One B-rep face of a CAD part: STEP entity #1033.
In plain terms, the planar face has unit normal (1, 0, 0).
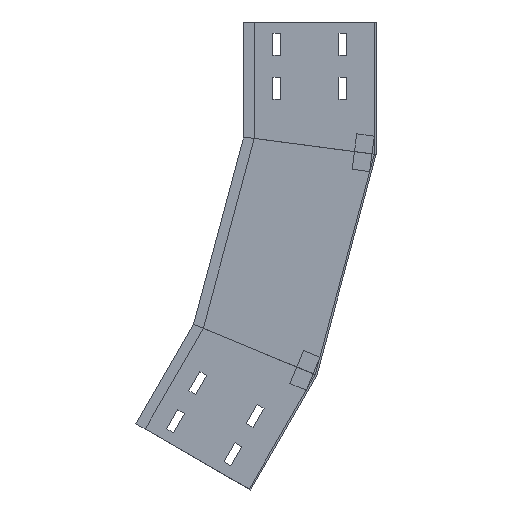
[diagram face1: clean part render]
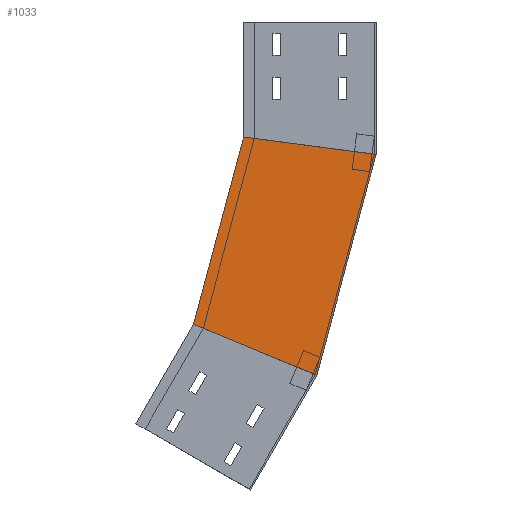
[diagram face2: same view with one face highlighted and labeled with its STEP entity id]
Its self-contained STEP definition (entity closure, numbers rounded to 3 decimals):
#41 = DIRECTION ( 'NONE',  ( 0., -0.991, -0.131 ) ) ;
#69 = ORIENTED_EDGE ( 'NONE', *, *, #1833, .F. ) ;
#74 = VECTOR ( 'NONE', #622, 1000. ) ;
#109 = CARTESIAN_POINT ( 'NONE',  ( 0., 0., -150. ) ) ;
#186 = LINE ( 'NONE', #1592, #74 ) ;
#189 = CARTESIAN_POINT ( 'NONE',  ( 0., 67.034, -400.175 ) ) ;
#223 = VERTEX_POINT ( 'NONE', #109 ) ;
#253 = VERTEX_POINT ( 'NONE', #1945 ) ;
#333 = ORIENTED_EDGE ( 'NONE', *, *, #902, .T. ) ;
#420 = LINE ( 'NONE', #1068, #1081 ) ;
#528 = CARTESIAN_POINT ( 'NONE',  ( 0., 150., -130.252 ) ) ;
#547 = LINE ( 'NONE', #556, #1337 ) ;
#556 = CARTESIAN_POINT ( 'NONE',  ( 0., 19.411, -147.444 ) ) ;
#579 = DIRECTION ( 'NONE',  ( 0., -0.924, -0.383 ) ) ;
#616 = DIRECTION ( 'NONE',  ( 0., 0., 1. ) ) ;
#622 = DIRECTION ( 'NONE',  ( 0., 0.259, -0.966 ) ) ;
#625 = DIRECTION ( 'NONE',  ( 0., 0.259, -0.966 ) ) ;
#752 = FACE_OUTER_BOUND ( 'NONE', #1947, .T. ) ;
#902 = EDGE_CURVE ( 'NONE', #223, #1470, #1321, .T. ) ;
#994 = VECTOR ( 'NONE', #625, 1000. ) ;
#1033 = ADVANCED_FACE ( 'NONE', ( #752 ), #1384, .F. ) ;
#1035 = ORIENTED_EDGE ( 'NONE', *, *, #1397, .F. ) ;
#1068 = CARTESIAN_POINT ( 'NONE',  ( 0., 98.267, -387.238 ) ) ;
#1078 = CARTESIAN_POINT ( 'NONE',  ( 0., 0., -150. ) ) ;
#1081 = VECTOR ( 'NONE', #579, 1000. ) ;
#1154 = VERTEX_POINT ( 'NONE', #528 ) ;
#1222 = DIRECTION ( 'NONE',  ( -1., 0., 0. ) ) ;
#1321 = LINE ( 'NONE', #1560, #994 ) ;
#1337 = VECTOR ( 'NONE', #41, 1000. ) ;
#1365 = AXIS2_PLACEMENT_3D ( 'NONE', #1078, #1222, #616 ) ;
#1384 = PLANE ( 'NONE',  #1365 ) ;
#1397 = EDGE_CURVE ( 'NONE', #253, #1470, #420, .T. ) ;
#1470 = VERTEX_POINT ( 'NONE', #189 ) ;
#1560 = CARTESIAN_POINT ( 'NONE',  ( 0., 0., -150. ) ) ;
#1592 = CARTESIAN_POINT ( 'NONE',  ( 0., 144.889, -111.177 ) ) ;
#1610 = EDGE_CURVE ( 'NONE', #1154, #223, #547, .T. ) ;
#1833 = EDGE_CURVE ( 'NONE', #1154, #253, #186, .T. ) ;
#1945 = CARTESIAN_POINT ( 'NONE',  ( 0., 206.812, -342.277 ) ) ;
#1947 = EDGE_LOOP ( 'NONE', ( #69, #2008, #333, #1035 ) ) ;
#2008 = ORIENTED_EDGE ( 'NONE', *, *, #1610, .T. ) ;
